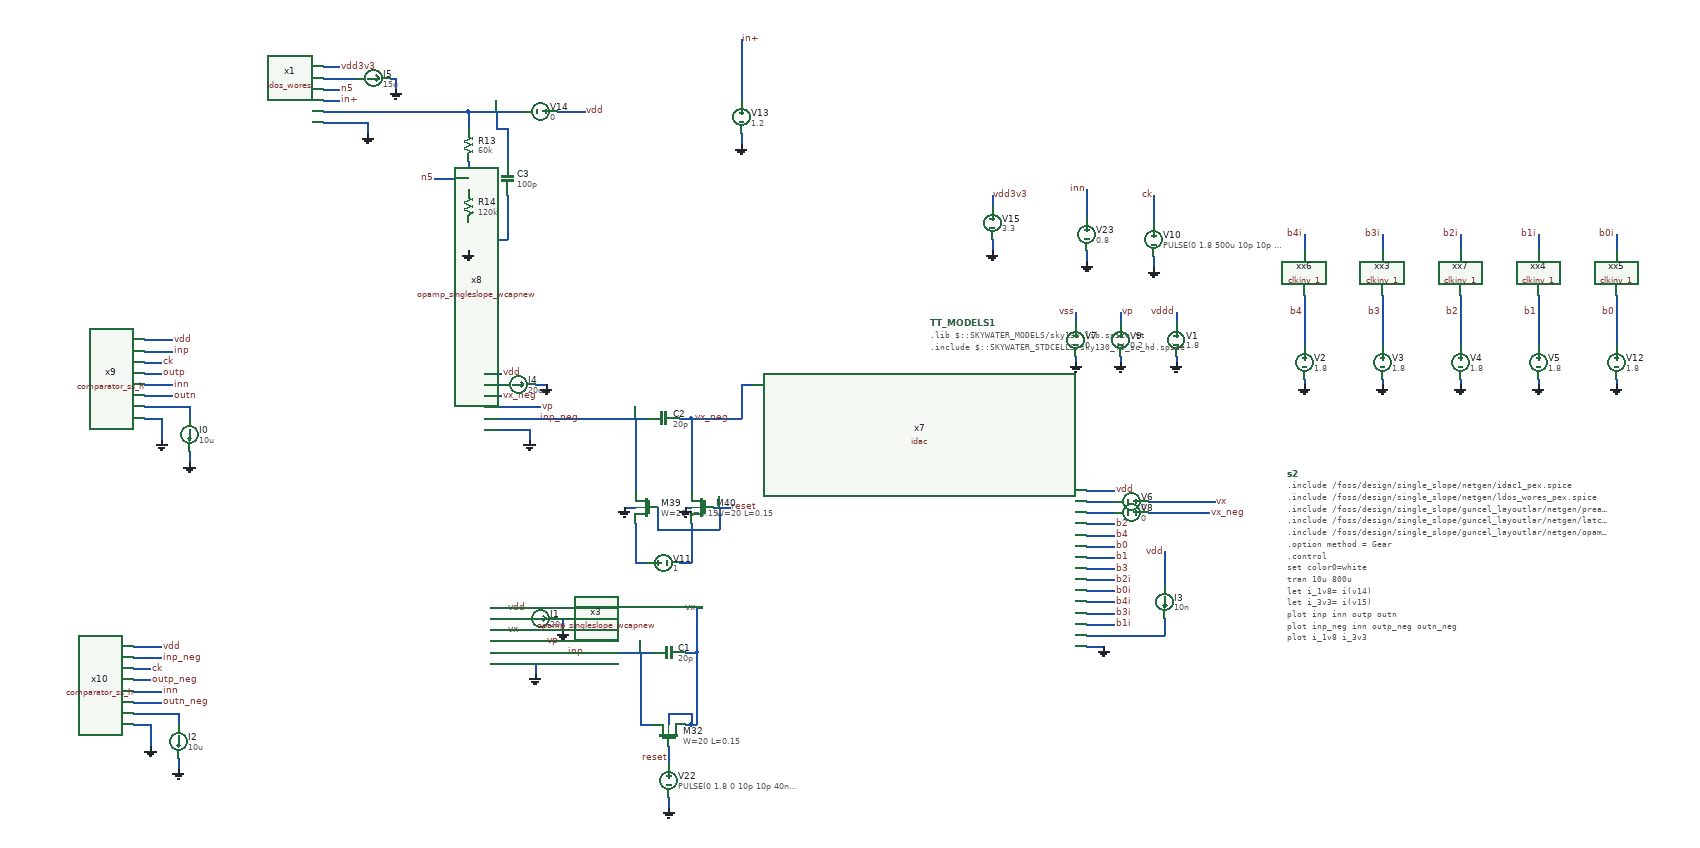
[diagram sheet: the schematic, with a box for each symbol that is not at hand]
v {xschem version=3.0.0 file_version=1.2 }
G {}
K {}
V {}
S {}
E {}
N 1460 -920 1460 -910 {
lab=GND}
N 1460 -1000 1460 -980 {
lab=vddd}
N 1360 -920 1360 -910 {
lab=GND}
N 1360 -1000 1360 -980 {
lab=vp}
N 1690 -1030 1690 -1000 {
lab=b4}
N 2110 -1030 2110 -1000 {
lab=b1}
N 1970 -1030 1970 -1000 {
lab=b2}
N 1830 -1030 1830 -1000 {
lab=b3}
N 2250 -1030 2250 -1000 {
lab=b0}
N 1690 -1140 1690 -1110 {
lab=b4i}
N 1830 -1140 1830 -1110 {
lab=b3i}
N 1970 -1140 1970 -1110 {
lab=b2i}
N 2110 -1140 2110 -1110 {
lab=b1i}
N 2250 -1140 2250 -1110 {
lab=b0i}
N 1280 -920 1280 -910 {
lab=GND}
N 1280 -1000 1280 -980 {
lab=vss}
N 1690 -880 1690 -870 {
lab=GND}
N 1690 -950 1690 -940 {
lab=b4}
N 1830 -880 1830 -870 {
lab=GND}
N 1970 -880 1970 -870 {
lab=GND}
N 2110 -880 2110 -870 {
lab=GND}
N 2250 -880 2250 -870 {
lab=GND}
N 1970 -950 1970 -940 {
lab=b2}
N 1830 -950 1830 -940 {
lab=b3}
N 2250 -950 2250 -940 {
lab=b0}
N 1970 -960 1970 -950 {
lab=b2}
N 1830 -960 1830 -950 {
lab=b3}
N 2250 -960 2250 -950 {
lab=b0}
N 1690 -1000 1690 -970 {
lab=b4}
N 2110 -1000 2110 -970 {
lab=b1}
N 1970 -970 1970 -960 {
lab=b2}
N 1830 -970 1830 -960 {
lab=b3}
N 1970 -1000 1970 -970 {
lab=b2}
N 1830 -1000 1830 -970 {
lab=b3}
N 2250 -970 2250 -960 {
lab=b0}
N 2250 -1000 2250 -970 {
lab=b0}
N 2110 -970 2110 -940 {
lab=b1}
N 1690 -970 1690 -950 {
lab=b4}
N 580 -390 600 -390 {
lab=vx}
N 600 -470 600 -390 {
lab=vx}
N 440 -390 520 -390 {
lab=inp}
N 500 -260 520 -260 {
lab=inp}
N 500 -390 500 -260 {
lab=inp}
N 580 -260 590 -260 {
lab=vx}
N 590 -260 600 -260 {
lab=vx}
N 600 -390 600 -260 {
lab=vx}
N 550 -280 550 -260 {
lab=vx}
N 550 -280 590 -280 {
lab=vx}
N 590 -280 590 -260 {
lab=vx}
N 550 -220 550 -190 {
lab=reset}
N 550 -130 550 -110 {
lab=GND}
N 340 -390 440 -390 {
lab=inp}
N 230 -470 260 -470 {
lab=vdd}
N 230 -430 260 -430 {
lab=vx}
N 230 -410 310 -410 {
lab=vp}
N 230 -390 250 -390 {
lab=inp}
N 230 -370 310 -370 {
lab=GND}
N 310 -370 310 -350 {
lab=GND}
N 250 -390 340 -390 {
lab=inp}
N 310 -410 330 -410 {
lab=vp}
N 360 -450 360 -430 {
lab=GND}
N 230 -450 290 -450 {
lab=#net1}
N 350 -450 360 -450 {
lab=GND}
N 570 -810 590 -810 {
lab=vx_neg}
N 430 -810 510 -810 {
lab=inp_neg}
N 490 -810 490 -680 {
lab=inp_neg}
N 590 -810 590 -680 {
lab=vx_neg}
N 330 -810 430 -810 {
lab=inp_neg}
N 220 -870 250 -870 {
lab=#net2}
N 220 -850 250 -850 {
lab=vx_neg}
N 220 -830 300 -830 {
lab=vp}
N 220 -810 240 -810 {
lab=inp_neg}
N 220 -790 300 -790 {
lab=GND}
N 300 -790 300 -770 {
lab=GND}
N 240 -810 330 -810 {
lab=inp_neg}
N 300 -830 320 -830 {
lab=vp}
N 490 -550 510 -550 {
lab=#net3}
N 570 -550 590 -550 {
lab=#net4}
N 490 -620 490 -550 {
lab=#net3}
N 590 -620 590 -550 {
lab=#net4}
N 470 -650 490 -650 {
lab=GND}
N 580 -650 590 -650 {
lab=GND}
N 630 -650 660 -650 {
lab=reset}
N 530 -650 530 -610 {
lab=reset}
N 530 -610 640 -610 {
lab=reset}
N 640 -650 640 -610 {
lab=reset}
N 590 -810 660 -810 {
lab=vx_neg}
N 220 -890 250 -890 {
lab=vdd}
N 310 -870 330 -870 {
lab=GND}
N 1300 -680 1350 -680 {
lab=vdd}
N 1300 -660 1350 -660 {
lab=#net5}
N 1300 -400 1330 -400 {
lab=GND}
N 1300 -620 1350 -620 {
lab=b2}
N 1300 -600 1350 -600 {
lab=b4}
N 1300 -580 1350 -580 {
lab=b0}
N 1300 -560 1350 -560 {
lab=b1}
N 1300 -540 1350 -540 {
lab=b3}
N 1300 -520 1350 -520 {
lab=b2i}
N 1300 -500 1350 -500 {
lab=b0i}
N 1300 -480 1350 -480 {
lab=b4i}
N 1300 -460 1350 -460 {
lab=b3i}
N 1300 -440 1350 -440 {
lab=b1i}
N 1300 -420 1350 -420 {
lab=#net6}
N 1440 -550 1440 -510 {
lab=vdd}
N 1440 -570 1440 -550 {
lab=vdd}
N 1350 -420 1440 -420 {
lab=#net6}
N 1420 -660 1450 -660 {
lab=vx}
N 1410 -660 1420 -660 {
lab=vx}
N 1410 -640 1450 -640 {
lab=vx_neg}
N 1300 -640 1350 -640 {
lab=#net7}
N 1420 -1100 1420 -1080 {
lab=GND}
N 1420 -1210 1420 -1160 {
lab=ck}
N 1300 -1110 1300 -1090 {
lab=GND}
N 1300 -1220 1300 -1170 {
lab=inn}
N 600 -470 610 -470 {
lab=vx}
N 660 -810 680 -810 {
lab=vx_neg}
N 680 -870 680 -810 {
lab=vx_neg}
N 680 -870 700 -870 {
lab=vx_neg}
N 1440 -450 1440 -420 {
lab=#net6}
N -360 -810 -360 -770 {
lab=GND}
N -390 -930 -340 -930 {
lab=inp}
N -390 -870 -340 -870 {
lab=inn}
N -390 -850 -340 -850 {
lab=outn}
N -390 -910 -360 -910 {
lab=ck}
N -390 -890 -360 -890 {
lab=outp}
N -390 -950 -340 -950 {
lab=vdd}
N -390 -810 -360 -810 {
lab=GND}
N -310 -830 -310 -810 {
lab=#net8}
N -310 -750 -310 -730 {
lab=GND}
N -390 -830 -310 -830 {
lab=#net8}
N -380 -260 -380 -220 {
lab=GND}
N -410 -380 -360 -380 {
lab=inp_neg}
N -410 -320 -360 -320 {
lab=inn}
N -410 -300 -360 -300 {
lab=outn_neg}
N -410 -360 -380 -360 {
lab=ck}
N -410 -340 -380 -340 {
lab=outp_neg}
N -410 -400 -360 -400 {
lab=vdd}
N -410 -260 -380 -260 {
lab=GND}
N -330 -280 -330 -260 {
lab=#net9}
N -330 -200 -330 -180 {
lab=GND}
N -410 -280 -330 -280 {
lab=#net9}
N 680 -1400 680 -1380 {
lab=in+}
N 680 -1320 680 -1300 {
lab=GND}
N 680 -1410 680 -1400 {
lab=in+}
N 680 -1420 680 -1410 {
lab=in+}
N 680 -1490 680 -1480 {
lab=in+}
N 680 -1480 680 -1420 {
lab=in+}
N 190 -1130 190 -1110 {
lab=GND}
N 190 -1270 190 -1220 {
lab=n5}
N 190 -1360 190 -1330 {
lab=#net10}
N 190 -1360 290 -1360 {
lab=#net10}
N 190 -1160 190 -1130 {
lab=GND}
N 130 -1240 190 -1240 {
lab=n5}
N 350 -1360 400 -1360 {
lab=vdd}
N 260 -1330 260 -1270 {
lab=#net10}
N 240 -1330 260 -1330 {
lab=#net10}
N 240 -1360 240 -1330 {
lab=#net10}
N 260 -1210 260 -1130 {
lab=GND}
N 190 -1130 260 -1130 {
lab=GND}
N -70 -1440 -40 -1440 {
lab=vdd3v3}
N -70 -1400 -40 -1400 {
lab=n5}
N -70 -1360 -50 -1360 {
lab=#net10}
N -70 -1340 10 -1340 {
lab=GND}
N 10 -1340 10 -1320 {
lab=GND}
N 60 -1420 60 -1400 {
lab=GND}
N -70 -1420 -10 -1420 {
lab=#net11}
N 50 -1420 60 -1420 {
lab=GND}
N -70 -1380 -40 -1380 {
lab=in+}
N -50 -1360 -40 -1360 {
lab=#net10}
N -40 -1360 80 -1360 {
lab=#net10}
N 80 -1360 130 -1360 {
lab=#net10}
N 130 -1360 190 -1360 {
lab=#net10}
N 1130 -1130 1130 -1110 {
lab=GND}
N 1130 -1210 1130 -1190 {
lab=vdd3v3}
N 1450 -660 1530 -660 {
lab=vx}
N 1450 -640 1520 -640 {
lab=vx_neg}
C {devices/code_shown.sym} 1660 -710 0 0 {name=s2 only_toplevel=false value="


.include /foss/design/single_slope/netgen/idac1_pex.spice
.include /foss/design/single_slope/netgen/ldos_wores_pex.spice
.include /foss/design/single_slope/guncel_layoutlar/netgen/preamp_singleslope_new_pex.spice
.include /foss/design/single_slope/guncel_layoutlar/netgen/latch_singleslope_new_pex.spice
.include /foss/design/single_slope/guncel_layoutlar/netgen/opamp_singleslope_addcap_pex.spice
.option method = Gear

.control
set color0=white

tran 10u 800u
let i_1v8= i(v14)
let i_3v3= i(v15)
plot inp inn outp outn
plot inp_neg inn outp_neg outn_neg
plot i_1v8 i_3v3

.endc
.end
"
}
C {devices/vsource.sym} 1460 -950 0 0 {name=V1 value=1.8}
C {devices/gnd.sym} 1460 -910 0 1 {name=l6 lab=GND}
C {devices/lab_pin.sym} 1460 -1000 0 0 {name=l7 sig_type=std_logic lab=vddd}
C {devices/code.sym} 1020 -980 0 0 {name=TT_MODELS1
only_toplevel=true
format="tcleval(@value )"
value=".lib $::SKYWATER_MODELS/sky130.lib.spice tt
.include $::SKYWATER_STDCELLS/sky130_fd_sc_hd.spice
"
spice_ignore=false
place=header}
C {devices/vsource.sym} 1360 -950 0 0 {name=V9 value=0.2}
C {devices/gnd.sym} 1360 -910 0 1 {name=l5 lab=GND}
C {pdk/sky130A/libs.tech/xschem/sky130_stdcells/clkinv_1.sym} 1690 -1070 3 0 {name=xx6 VGND=vss VNB=vss VPB=vddd VPWR=vddd prefix=sky130_fd_sc_hd__ }
C {devices/lab_pin.sym} 1690 -1140 0 0 {name=p6 sig_type=std_logic lab=b4i
}
C {devices/lab_pin.sym} 1830 -1140 0 0 {name=p7 sig_type=std_logic lab=b3i
}
C {devices/lab_pin.sym} 1970 -1140 0 0 {name=p8 sig_type=std_logic lab=b2i
}
C {devices/lab_pin.sym} 2110 -1140 0 0 {name=p9 sig_type=std_logic lab=b1i
}
C {devices/lab_pin.sym} 2250 -1140 0 0 {name=p16 sig_type=std_logic lab=b0i
}
C {pdk/sky130A/libs.tech/xschem/sky130_stdcells/clkinv_1.sym} 2110 -1070 3 0 {name=xx4 VGND=vss VNB=vss VPB=vddd VPWR=vddd prefix=sky130_fd_sc_hd__ }
C {pdk/sky130A/libs.tech/xschem/sky130_stdcells/clkinv_1.sym} 2250 -1070 3 0 {name=xx5 VGND=vss VNB=vss VPB=vddd VPWR=vddd prefix=sky130_fd_sc_hd__ }
C {devices/vsource.sym} 1280 -950 0 0 {name=V7 value=0}
C {devices/gnd.sym} 1280 -910 0 1 {name=l53 lab=GND}
C {devices/lab_pin.sym} 1280 -1000 0 0 {name=l54 sig_type=std_logic lab=vss}
C {devices/vsource.sym} 1690 -910 0 0 {name=V2 value= 1.8
*"PULSE(1.8 0 0 1n 1n 4096u 8192u)" savecurrent=false}
C {devices/gnd.sym} 1690 -870 0 1 {name=l4 lab=GND}
C {devices/gnd.sym} 1830 -870 0 1 {name=l24 lab=GND}
C {devices/gnd.sym} 1970 -870 0 1 {name=l25 lab=GND}
C {devices/gnd.sym} 2110 -870 0 1 {name=l26 lab=GND}
C {devices/gnd.sym} 2250 -870 0 1 {name=l27 lab=GND}
C {devices/lab_pin.sym} 1690 -1000 0 0 {name=p11 sig_type=std_logic lab=b4
}
C {devices/vsource.sym} 1830 -910 0 0 {name=V3 value= 1.8
*"PULSE(1.8 0 0 1n 1n 2048u 4096u)" savecurrent=false}
C {devices/vsource.sym} 1970 -910 0 0 {name=V4 value=1.8
*"PULSE(1.8 0 0 1n 1n 1024u 2048u)" savecurrent=false}
C {devices/vsource.sym} 2110 -910 0 0 {name=V5 value=1.8
*"PULSE(1.8 0 0 1n 1n 512u 1024u)" savecurrent=false}
C {devices/vsource.sym} 2250 -910 0 0 {name=V12 value=1.8
*"PULSE(1.8 0 0 1n 1n 256u 512u)" savecurrent=false}
C {devices/lab_pin.sym} 2110 -1000 0 0 {name=p12 sig_type=std_logic lab=b1
}
C {devices/lab_pin.sym} 1830 -1000 0 0 {name=p13 sig_type=std_logic lab=b3
}
C {devices/lab_pin.sym} 1970 -1000 0 0 {name=p14 sig_type=std_logic lab=b2
}
C {devices/lab_pin.sym} 2250 -1000 0 0 {name=p15 sig_type=std_logic lab=b0
}
C {devices/lab_pin.sym} 1360 -1000 2 0 {name=l59 sig_type=std_logic lab=vp}
C {devices/capa.sym} 550 -390 1 0 {name=C1
m=1
value=20p
footprint=1206
device="ceramic capacitor"}
C {devices/lab_pin.sym} 600 -470 1 0 {name=l80 sig_type=std_logic lab=vx}
C {pdk/sky130A/libs.tech/xschem/sky130_fd_pr/nfet_01v8.sym} 550 -240 3 0 {name=M32
L=0.15
W=20
nf=1 
mult=2
ad="'int((nf+1)/2) * W/nf * 0.29'" 
pd="'2*int((nf+1)/2) * (W/nf + 0.29)'"
as="'int((nf+2)/2) * W/nf * 0.29'" 
ps="'2*int((nf+2)/2) * (W/nf + 0.29)'"
nrd="'0.29 / W'" nrs="'0.29 / W'"
sa=0 sb=0 sd=0
model=nfet_01v8
spiceprefix=X
}
C {devices/vsource.sym} 550 -160 0 0 {name=V22 value="PULSE(0 1.8 0 10p 10p 40n 256.04u)"}
C {devices/gnd.sym} 550 -110 0 0 {name=l81 lab=GND}
C {devices/lab_pin.sym} 260 -470 2 0 {name=l82 sig_type=std_logic lab=vdd}
C {devices/lab_pin.sym} 550 -200 0 0 {name=l83 sig_type=std_logic lab=reset}
C {devices/lab_pin.sym} 260 -430 2 0 {name=l84 sig_type=std_logic lab=vx}
C {devices/gnd.sym} 310 -350 0 0 {name=l85 lab=GND}
C {devices/lab_pin.sym} 400 -390 1 0 {name=l86 sig_type=std_logic lab=inp}
C {devices/isource.sym} 320 -450 3 0 {name=I1 value=20u}
C {devices/gnd.sym} 360 -430 0 0 {name=l87 lab=GND}
C {design/single_slope/opamp_singleslope_wcapnew.sym} 80 -420 0 0 {name=x3}
C {devices/lab_pin.sym} 330 -410 0 1 {name=l88 sig_type=std_logic lab=vp}
C {devices/capa.sym} 540 -810 1 0 {name=C2
m=1
value=20p
footprint=1206
device="ceramic capacitor"}
C {devices/lab_pin.sym} 660 -810 1 0 {name=l97 sig_type=std_logic lab=vx_neg}
C {devices/lab_pin.sym} 250 -890 2 0 {name=l98 sig_type=std_logic lab=vdd}
C {devices/lab_pin.sym} 250 -850 2 0 {name=l99 sig_type=std_logic lab=vx_neg}
C {devices/gnd.sym} 300 -770 0 0 {name=l100 lab=GND}
C {devices/lab_pin.sym} 390 -810 1 0 {name=l101 sig_type=std_logic lab=inp_neg}
C {devices/vsource.sym} 540 -550 3 0 {name=V11 value=1}
C {devices/lab_pin.sym} 660 -650 0 1 {name=l102 sig_type=std_logic lab=reset}
C {pdk/sky130A/libs.tech/xschem/sky130_fd_pr/nfet_01v8.sym} 510 -650 2 0 {name=M39
L=0.15
W=20
nf=1 
mult=2
ad="'int((nf+1)/2) * W/nf * 0.29'" 
pd="'2*int((nf+1)/2) * (W/nf + 0.29)'"
as="'int((nf+2)/2) * W/nf * 0.29'" 
ps="'2*int((nf+2)/2) * (W/nf + 0.29)'"
nrd="'0.29 / W'" nrs="'0.29 / W'"
sa=0 sb=0 sd=0
model=nfet_01v8
spiceprefix=X
}
C {pdk/sky130A/libs.tech/xschem/sky130_fd_pr/nfet_01v8.sym} 610 -650 2 0 {name=M40
L=0.15
W=20
nf=1 
mult=2
ad="'int((nf+1)/2) * W/nf * 0.29'" 
pd="'2*int((nf+1)/2) * (W/nf + 0.29)'"
as="'int((nf+2)/2) * W/nf * 0.29'" 
ps="'2*int((nf+2)/2) * (W/nf + 0.29)'"
nrd="'0.29 / W'" nrs="'0.29 / W'"
sa=0 sb=0 sd=0
model=nfet_01v8
spiceprefix=X
}
C {devices/gnd.sym} 470 -650 0 0 {name=l103 lab=GND}
C {devices/gnd.sym} 580 -650 0 0 {name=l104 lab=GND}
C {devices/lab_pin.sym} 320 -830 0 1 {name=l105 sig_type=std_logic lab=vp}
C {design/single_slope/opamp_singleslope_wcapnew.sym} 70 -840 0 0 {name=x8}
C {devices/isource.sym} 280 -870 3 0 {name=I4 value=20u}
C {devices/gnd.sym} 330 -870 0 0 {name=l106 lab=GND}
C {devices/lab_pin.sym} 1350 -680 2 0 {name=l76 sig_type=std_logic lab=vdd}
C {devices/lab_pin.sym} 1530 -660 2 0 {name=l79 sig_type=std_logic lab=vx}
C {devices/lab_pin.sym} 1520 -640 2 0 {name=l107 sig_type=std_logic lab=vx_neg}
C {devices/lab_pin.sym} 1350 -620 2 0 {name=l109 sig_type=std_logic lab=b2}
C {devices/lab_pin.sym} 1350 -600 2 0 {name=l110 sig_type=std_logic lab=b4}
C {devices/lab_pin.sym} 1350 -580 2 0 {name=l111 sig_type=std_logic lab=b0}
C {devices/lab_pin.sym} 1350 -560 2 0 {name=l112 sig_type=std_logic lab=b1}
C {devices/lab_pin.sym} 1350 -540 2 0 {name=l113 sig_type=std_logic lab=b3}
C {devices/lab_pin.sym} 1350 -520 2 0 {name=l114 sig_type=std_logic lab=b2i}
C {devices/lab_pin.sym} 1350 -500 2 0 {name=l115 sig_type=std_logic lab=b0i}
C {devices/lab_pin.sym} 1350 -480 2 0 {name=l116 sig_type=std_logic lab=b4i}
C {devices/lab_pin.sym} 1350 -460 2 0 {name=l117 sig_type=std_logic lab=b3i}
C {devices/lab_pin.sym} 1350 -440 2 0 {name=l118 sig_type=std_logic lab=b1i}
C {devices/isource.sym} 1440 -480 0 0 {name=I3 value=10n}
C {devices/lab_pin.sym} 1440 -570 0 0 {name=l119 sig_type=std_logic lab=vdd}
C {design/single_slope/idac.sym} 1150 -540 0 0 {name=x7}
C {devices/gnd.sym} 1330 -400 0 0 {name=l15 lab=GND}
C {devices/vsource.sym} 1420 -1130 0 0 {name=V10 value="PULSE(0 1.8 500u 10p 10p .5u 1u)"
}
C {devices/gnd.sym} 1420 -1080 0 0 {name=l123 lab=GND}
C {devices/lab_pin.sym} 1420 -1210 0 0 {name=l124 sig_type=std_logic lab=ck}
C {devices/vsource.sym} 1300 -1140 0 0 {name=V23 value=0.8}
C {devices/gnd.sym} 1300 -1090 0 0 {name=l125 lab=GND}
C {devices/lab_pin.sym} 1300 -1220 0 0 {name=l126 sig_type=std_logic lab=inn}
C {devices/vsource.sym} 1380 -660 1 0 {name=V6 value=0}
C {devices/vsource.sym} 1380 -640 1 0 {name=V8 value=0}
C {devices/gnd.sym} -360 -770 0 0 {name=l1 lab=GND}
C {devices/lab_pin.sym} -340 -950 0 1 {name=l2 sig_type=std_logic lab=vdd}
C {devices/lab_pin.sym} -360 -910 0 1 {name=l3 sig_type=std_logic lab=ck}
C {devices/lab_pin.sym} -340 -930 0 1 {name=l108 sig_type=std_logic lab=inp}
C {devices/lab_pin.sym} -340 -870 0 1 {name=l8 sig_type=std_logic lab=inn}
C {devices/lab_pin.sym} -360 -890 0 1 {name=l9 sig_type=std_logic lab=outp}
C {devices/lab_pin.sym} -340 -850 0 1 {name=l10 sig_type=std_logic lab=outn}
C {devices/isource.sym} -310 -780 0 0 {name=I0 value=10u}
C {devices/gnd.sym} -310 -730 0 0 {name=l11 lab=GND}
C {design/single_slope/comparator_ss_h.sym} -540 -880 0 0 {name=x9}
C {devices/gnd.sym} -380 -220 0 0 {name=l19 lab=GND}
C {devices/lab_pin.sym} -360 -400 0 1 {name=l20 sig_type=std_logic lab=vdd}
C {devices/lab_pin.sym} -380 -360 0 1 {name=l21 sig_type=std_logic lab=ck}
C {devices/lab_pin.sym} -360 -380 0 1 {name=l22 sig_type=std_logic lab=inp_neg}
C {devices/lab_pin.sym} -360 -320 0 1 {name=l12 sig_type=std_logic lab=inn}
C {devices/lab_pin.sym} -380 -340 0 1 {name=l13 sig_type=std_logic lab=outp_neg}
C {devices/lab_pin.sym} -360 -300 0 1 {name=l30 sig_type=std_logic lab=outn_neg}
C {devices/isource.sym} -330 -230 0 0 {name=I2 value=10u}
C {devices/gnd.sym} -330 -180 0 0 {name=l31 lab=GND}
C {design/single_slope/comparator_ss_h.sym} -560 -330 0 0 {name=x10}
C {pdk/sky130A/libs.tech/xschem/sky130_stdcells/clkinv_1.sym} 1970 -1070 3 0 {name=xx7 VGND=vss VNB=vss VPB=vddd VPWR=vddd prefix=sky130_fd_sc_hd__ }
C {pdk/sky130A/libs.tech/xschem/sky130_stdcells/clkinv_1.sym} 1830 -1070 3 0 {name=xx3 VGND=vss VNB=vss VPB=vddd VPWR=vddd prefix=sky130_fd_sc_hd__ }
C {devices/vsource.sym} 680 -1350 0 0 {name=V13 value=1.2}
C {devices/gnd.sym} 680 -1300 0 0 {name=l14 lab=GND}
C {devices/lab_pin.sym} 680 -1490 2 0 {name=l16 sig_type=std_logic lab=in+}
C {devices/gnd.sym} 190 -1110 0 0 {name=l156 lab=GND}
C {devices/res.sym} 190 -1300 0 0 {name=R13
value=60k
footprint=1206
device=resistor
m=1}
C {devices/res.sym} 190 -1190 0 0 {name=R14
value=120k
footprint=1206
device=resistor
m=1}
C {devices/lab_pin.sym} 130 -1240 0 0 {name=l17 sig_type=std_logic lab=n5}
C {devices/lab_pin.sym} 400 -1360 0 1 {name=l18 sig_type=std_logic lab=vdd}
C {devices/vsource.sym} 320 -1360 1 0 {name=V14 value=0}
C {devices/capa.sym} 260 -1240 0 0 {name=C3
m=1
value=100p
footprint=1206
device="ceramic capacitor"}
C {devices/lab_pin.sym} -40 -1440 2 0 {name=l23 sig_type=std_logic lab=vdd3v3}
C {devices/lab_pin.sym} -40 -1400 2 0 {name=l28 sig_type=std_logic lab=n5}
C {devices/gnd.sym} 10 -1320 0 0 {name=l29 lab=GND}
C {devices/lab_pin.sym} -40 -1380 2 0 {name=l32 sig_type=std_logic lab=in+}
C {devices/isource.sym} 20 -1420 3 0 {name=I5 value=15u}
C {devices/gnd.sym} 60 -1400 0 0 {name=l33 lab=GND}
C {design/ldo/ldos_wores.sym} -220 -1390 0 0 {name=x1}
C {devices/vsource.sym} 1130 -1160 0 0 {name=V15 value=3.3}
C {devices/gnd.sym} 1130 -1110 0 0 {name=l34 lab=GND}
C {devices/lab_pin.sym} 1130 -1210 0 1 {name=l35 sig_type=std_logic lab=vdd3v3}
